! (c) 2009  Infineon Technologies AG, Munich
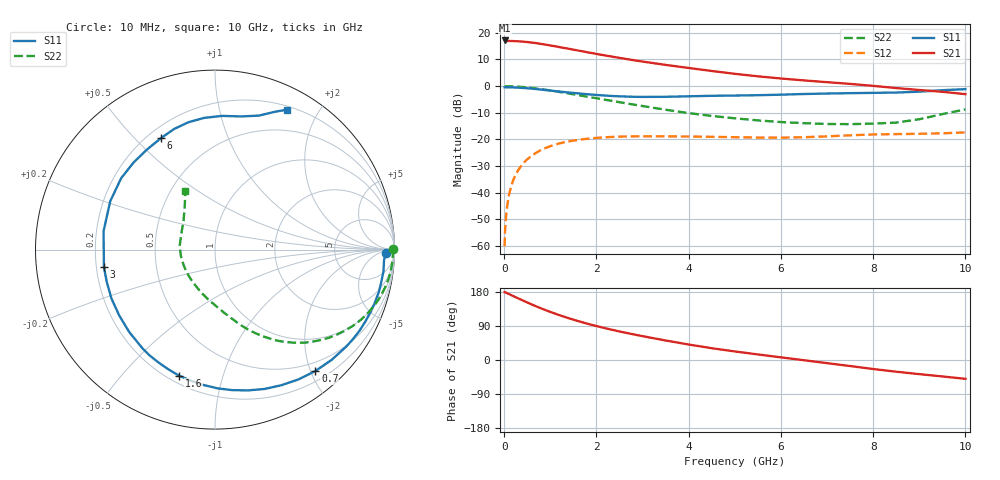
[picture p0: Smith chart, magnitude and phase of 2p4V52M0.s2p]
! Infineon Technologies  Discrete & RF Semiconductors
! BFP420
! VCE =  4.5 V,  IC =  2.0 mA
! Common Emitter S-Parameters:  Nov 2009
# GHz  S  MA  R  50
!  f  S11  S21  S12  S22
! GHz  MAG  ANG  MAG  ANG  MAG  ANG  MAG  ANG
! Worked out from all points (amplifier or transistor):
!   46 points, 10 MHz to 10 GHz, reference 50 ohm
!   highest |S21| = 17.1 dB at 10 MHz (marker M1)
!   |S21| within 3 dB of that: start of sweep to 1.361 GHz
!   unconditionally stable (mu >= 1): 3.959 GHz to end of sweep
!   at 300 MHz: K = 0.07, MSG = 24.2 dB, |S12| = -31.7 dB
!   at 1.7 GHz: K = 0.34, MSG = 16.5 dB, |S12| = -19.9 dB
!   at 10 GHz: K = 1.22, MAG = 4.4 dB, |S12| = -17.4 dB
!   lowest NFmin = 0.53 dB at 900 MHz
!   S11 on the Smith chart (normalised r, x): 10 MHz: 35, -12; 700 MHz: 0.35, -2.08; 1.6 GHz: 0.24, -0.73; 3 GHz: 0.23, -0.07; 6 GHz: 0.25, +0.60; 10 GHz: 0.24, +1.61
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0.01  0.9501 -1.0  7.155 179.1  0.001 23.5  0.9917 0.1
0.02  0.9503 -1.5  6.94 179.0  0.002 63.6  0.9911 -0.7
0.05  0.9437 -3.6  6.97 177.0  0.0045 74.1  0.9916 -1.8
0.15  0.9439 -11.0  6.997 171.4  0.0131 80.2  0.9879 -5.8
0.4  0.9235 -29.2  6.804 157.4  0.0343 72.2  0.9602 -15.2
0.6  0.8944 -43.4  6.526 146.4  0.0498 64.8  0.9235 -22.3
0.7  0.8777 -50.4  6.367 141.3  0.0568 61.0  0.9011 -25.8
0.9  0.8414 -63.9  5.975 131.5  0.0692 54.1  0.8527 -32.0
1.1  0.806 -76.7  5.574 122.6  0.0797 47.8  0.8018 -37.8
1.3  0.7732 -88.9  5.181 114.2  0.0883 42.0  0.7507 -43.0
1.6  0.7301 -106.0  4.639 102.8  0.098 34.3  0.6778 -49.9
1.7  0.7152 -111.5  4.475 99.4  0.1008 32.0  0.6552 -51.9
2  0.6821 -126.5  4.002 89.7  0.1068 25.7  0.5922 -57.5
2.4  0.6475 -145.6  3.488 78.0  0.112 18.4  0.5161 -64.3
3  0.6265 -171.0  2.879 62.9  0.1146 9.8  0.4227 -73.3
3.5  0.6293 170.6  2.494 51.5  0.1143 4.3  0.3601 -81.1
4.5  0.657 142.7  1.918 31.1  0.1119 -3.0  0.2756 -99.2
5.5  0.6742 124.2  1.523 14.7  0.1084 -6.6  0.2274 -118.9
6  0.69 115.9  1.386 7.0  0.108 -7.0  0.2117 -130.4
7  0.7249 101.8  1.183 -8.3  0.1141 -7.9  0.1945 -155.2
8.5  0.7561 78.9  0.917 -30.9  0.1259 -14.9  0.2067 155.5
10  0.8763 62.8  0.706 -49.7  0.1353 -19.3  0.3656 116.9
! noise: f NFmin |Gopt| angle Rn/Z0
0.9  0.53  0.47  33  0.22
1.8  1.03  0.29  77  0.17
2.4  1.13  0.31  102  0.16
3  1.32  0.31  136  0.12
4  1.57  0.37  -168  0.1
5  1.96  0.42  -129  0.28
6  2.72  0.51  -111  0.37
